VERSION 5.7 ;
  NOWIREEXTENSIONATPIN ON ;
  DIVIDERCHAR "/" ;
  BUSBITCHARS "[]" ;
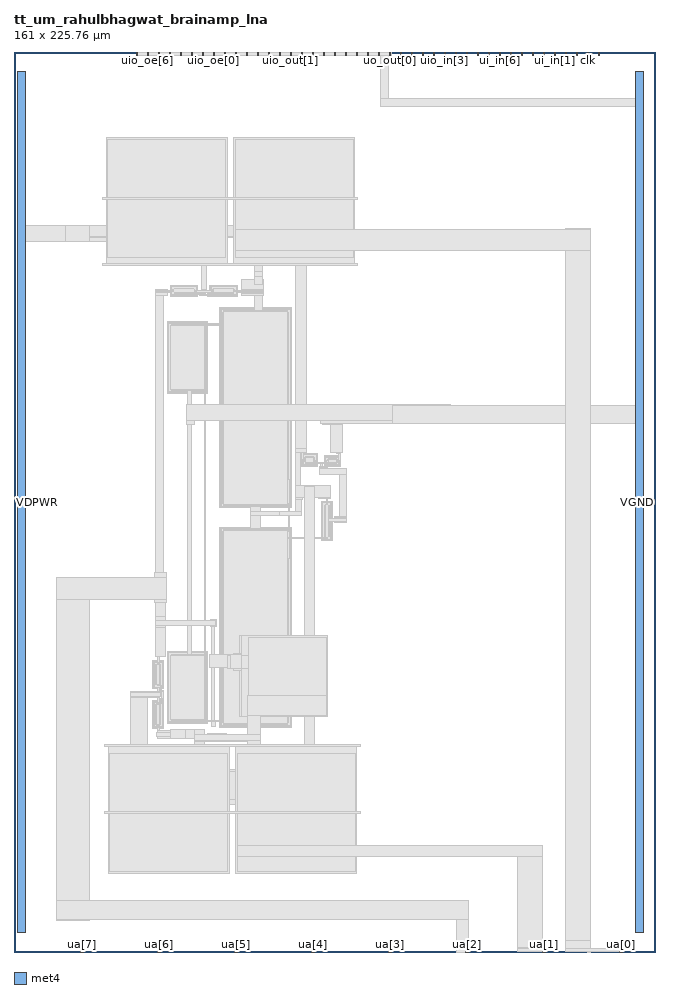
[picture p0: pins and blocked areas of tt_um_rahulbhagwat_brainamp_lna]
MACRO tt_um_rahulbhagwat_brainamp_lna
  CLASS BLOCK ;
  FOREIGN tt_um_rahulbhagwat_brainamp_lna ;
  ORIGIN 0.000 0.000 ;
  SIZE 161.000 BY 225.760 ;
  PIN clk
    DIRECTION INPUT ;
    USE SIGNAL ;
    PORT
      LAYER met4 ;
        RECT 143.830 224.760 144.130 225.760 ;
    END
  END clk
  PIN ena
    DIRECTION INPUT ;
    USE SIGNAL ;
    PORT
      LAYER met4 ;
        RECT 146.590 224.760 146.890 225.760 ;
    END
  END ena
  PIN rst_n
    DIRECTION INPUT ;
    USE SIGNAL ;
    PORT
      LAYER met4 ;
        RECT 141.070 224.760 141.370 225.760 ;
    END
  END rst_n
  PIN ua[0]
    DIRECTION INOUT ;
    USE SIGNAL ;
    PORT
      LAYER met4 ;
        RECT 151.810 0.000 152.710 1.000 ;
    END
  END ua[0]
  PIN ua[1]
    DIRECTION INOUT ;
    USE SIGNAL ;
    PORT
      LAYER met4 ;
        RECT 132.490 0.000 133.390 1.000 ;
    END
  END ua[1]
  PIN ua[2]
    DIRECTION INOUT ;
    USE SIGNAL ;
    ANTENNADIFFAREA 16.529999 ;
    PORT
      LAYER met4 ;
        RECT 113.170 0.000 114.070 1.000 ;
    END
  END ua[2]
  PIN ua[3]
    DIRECTION INOUT ;
    USE SIGNAL ;
    PORT
      LAYER met4 ;
        RECT 93.850 0.000 94.750 1.000 ;
    END
  END ua[3]
  PIN ua[4]
    DIRECTION INOUT ;
    USE SIGNAL ;
    PORT
      LAYER met4 ;
        RECT 74.530 0.000 75.430 1.000 ;
    END
  END ua[4]
  PIN ua[5]
    DIRECTION INOUT ;
    USE SIGNAL ;
    PORT
      LAYER met4 ;
        RECT 55.210 0.000 56.110 1.000 ;
    END
  END ua[5]
  PIN ua[6]
    DIRECTION INOUT ;
    USE SIGNAL ;
    PORT
      LAYER met4 ;
        RECT 35.890 0.000 36.790 1.000 ;
    END
  END ua[6]
  PIN ua[7]
    DIRECTION INOUT ;
    USE SIGNAL ;
    PORT
      LAYER met4 ;
        RECT 16.570 0.000 17.470 1.000 ;
    END
  END ua[7]
  PIN ui_in[0]
    DIRECTION INPUT ;
    USE SIGNAL ;
    PORT
      LAYER met4 ;
        RECT 138.310 224.760 138.610 225.760 ;
    END
  END ui_in[0]
  PIN ui_in[1]
    DIRECTION INPUT ;
    USE SIGNAL ;
    PORT
      LAYER met4 ;
        RECT 135.550 224.760 135.850 225.760 ;
    END
  END ui_in[1]
  PIN ui_in[2]
    DIRECTION INPUT ;
    USE SIGNAL ;
    PORT
      LAYER met4 ;
        RECT 132.790 224.760 133.090 225.760 ;
    END
  END ui_in[2]
  PIN ui_in[3]
    DIRECTION INPUT ;
    USE SIGNAL ;
    PORT
      LAYER met4 ;
        RECT 130.030 224.760 130.330 225.760 ;
    END
  END ui_in[3]
  PIN ui_in[4]
    DIRECTION INPUT ;
    USE SIGNAL ;
    PORT
      LAYER met4 ;
        RECT 127.270 224.760 127.570 225.760 ;
    END
  END ui_in[4]
  PIN ui_in[5]
    DIRECTION INPUT ;
    USE SIGNAL ;
    PORT
      LAYER met4 ;
        RECT 124.510 224.760 124.810 225.760 ;
    END
  END ui_in[5]
  PIN ui_in[6]
    DIRECTION INPUT ;
    USE SIGNAL ;
    PORT
      LAYER met4 ;
        RECT 121.750 224.760 122.050 225.760 ;
    END
  END ui_in[6]
  PIN ui_in[7]
    DIRECTION INPUT ;
    USE SIGNAL ;
    PORT
      LAYER met4 ;
        RECT 118.990 224.760 119.290 225.760 ;
    END
  END ui_in[7]
  PIN uio_in[0]
    DIRECTION INPUT ;
    USE SIGNAL ;
    PORT
      LAYER met4 ;
        RECT 116.230 224.760 116.530 225.760 ;
    END
  END uio_in[0]
  PIN uio_in[1]
    DIRECTION INPUT ;
    USE SIGNAL ;
    PORT
      LAYER met4 ;
        RECT 113.470 224.760 113.770 225.760 ;
    END
  END uio_in[1]
  PIN uio_in[2]
    DIRECTION INPUT ;
    USE SIGNAL ;
    PORT
      LAYER met4 ;
        RECT 110.710 224.760 111.010 225.760 ;
    END
  END uio_in[2]
  PIN uio_in[3]
    DIRECTION INPUT ;
    USE SIGNAL ;
    PORT
      LAYER met4 ;
        RECT 107.950 224.760 108.250 225.760 ;
    END
  END uio_in[3]
  PIN uio_in[4]
    DIRECTION INPUT ;
    USE SIGNAL ;
    PORT
      LAYER met4 ;
        RECT 105.190 224.760 105.490 225.760 ;
    END
  END uio_in[4]
  PIN uio_in[5]
    DIRECTION INPUT ;
    USE SIGNAL ;
    PORT
      LAYER met4 ;
        RECT 102.430 224.760 102.730 225.760 ;
    END
  END uio_in[5]
  PIN uio_in[6]
    DIRECTION INPUT ;
    USE SIGNAL ;
    PORT
      LAYER met4 ;
        RECT 99.670 224.760 99.970 225.760 ;
    END
  END uio_in[6]
  PIN uio_in[7]
    DIRECTION INPUT ;
    USE SIGNAL ;
    PORT
      LAYER met4 ;
        RECT 96.910 224.760 97.210 225.760 ;
    END
  END uio_in[7]
  PIN uio_oe[0]
    DIRECTION OUTPUT ;
    USE SIGNAL ;
    ANTENNADIFFAREA 25.014999 ;
    PORT
      LAYER met4 ;
        RECT 49.990 224.760 50.290 225.760 ;
    END
  END uio_oe[0]
  PIN uio_oe[1]
    DIRECTION OUTPUT ;
    USE SIGNAL ;
    PORT
      LAYER met4 ;
        RECT 47.230 224.760 47.530 225.760 ;
    END
  END uio_oe[1]
  PIN uio_oe[2]
    DIRECTION OUTPUT ;
    USE SIGNAL ;
    PORT
      LAYER met4 ;
        RECT 44.470 224.760 44.770 225.760 ;
    END
  END uio_oe[2]
  PIN uio_oe[3]
    DIRECTION OUTPUT ;
    USE SIGNAL ;
    PORT
      LAYER met4 ;
        RECT 41.710 224.760 42.010 225.760 ;
    END
  END uio_oe[3]
  PIN uio_oe[4]
    DIRECTION OUTPUT ;
    USE SIGNAL ;
    PORT
      LAYER met4 ;
        RECT 38.950 224.760 39.250 225.760 ;
    END
  END uio_oe[4]
  PIN uio_oe[5]
    DIRECTION OUTPUT ;
    USE SIGNAL ;
    PORT
      LAYER met4 ;
        RECT 36.190 224.760 36.490 225.760 ;
    END
  END uio_oe[5]
  PIN uio_oe[6]
    DIRECTION OUTPUT ;
    USE SIGNAL ;
    PORT
      LAYER met4 ;
        RECT 33.430 224.760 33.730 225.760 ;
    END
  END uio_oe[6]
  PIN uio_oe[7]
    DIRECTION OUTPUT ;
    USE SIGNAL ;
    PORT
      LAYER met4 ;
        RECT 30.670 224.760 30.970 225.760 ;
    END
  END uio_oe[7]
  PIN uio_out[0]
    DIRECTION OUTPUT ;
    USE SIGNAL ;
    ANTENNADIFFAREA 25.014999 ;
    PORT
      LAYER met4 ;
        RECT 72.070 224.760 72.370 225.760 ;
    END
  END uio_out[0]
  PIN uio_out[1]
    DIRECTION OUTPUT ;
    USE SIGNAL ;
    PORT
      LAYER met4 ;
        RECT 69.310 224.760 69.610 225.760 ;
    END
  END uio_out[1]
  PIN uio_out[2]
    DIRECTION OUTPUT ;
    USE SIGNAL ;
    PORT
      LAYER met4 ;
        RECT 66.550 224.760 66.850 225.760 ;
    END
  END uio_out[2]
  PIN uio_out[3]
    DIRECTION OUTPUT ;
    USE SIGNAL ;
    PORT
      LAYER met4 ;
        RECT 63.790 224.760 64.090 225.760 ;
    END
  END uio_out[3]
  PIN uio_out[4]
    DIRECTION OUTPUT ;
    USE SIGNAL ;
    PORT
      LAYER met4 ;
        RECT 61.030 224.760 61.330 225.760 ;
    END
  END uio_out[4]
  PIN uio_out[5]
    DIRECTION OUTPUT ;
    USE SIGNAL ;
    PORT
      LAYER met4 ;
        RECT 58.270 224.760 58.570 225.760 ;
    END
  END uio_out[5]
  PIN uio_out[6]
    DIRECTION OUTPUT ;
    USE SIGNAL ;
    PORT
      LAYER met4 ;
        RECT 55.510 224.760 55.810 225.760 ;
    END
  END uio_out[6]
  PIN uio_out[7]
    DIRECTION OUTPUT ;
    USE SIGNAL ;
    PORT
      LAYER met4 ;
        RECT 52.750 224.760 53.050 225.760 ;
    END
  END uio_out[7]
  PIN uo_out[0]
    DIRECTION OUTPUT ;
    USE SIGNAL ;
    ANTENNADIFFAREA 25.014999 ;
    PORT
      LAYER met4 ;
        RECT 94.150 224.760 94.450 225.760 ;
    END
  END uo_out[0]
  PIN uo_out[1]
    DIRECTION OUTPUT ;
    USE SIGNAL ;
    ANTENNADIFFAREA 25.014999 ;
    PORT
      LAYER met4 ;
        RECT 91.390 224.760 91.690 225.760 ;
    END
  END uo_out[1]
  PIN uo_out[2]
    DIRECTION OUTPUT ;
    USE SIGNAL ;
    PORT
      LAYER met4 ;
        RECT 88.630 224.760 88.930 225.760 ;
    END
  END uo_out[2]
  PIN uo_out[3]
    DIRECTION OUTPUT ;
    USE SIGNAL ;
    PORT
      LAYER met4 ;
        RECT 85.870 224.760 86.170 225.760 ;
    END
  END uo_out[3]
  PIN uo_out[4]
    DIRECTION OUTPUT ;
    USE SIGNAL ;
    PORT
      LAYER met4 ;
        RECT 83.110 224.760 83.410 225.760 ;
    END
  END uo_out[4]
  PIN uo_out[5]
    DIRECTION OUTPUT ;
    USE SIGNAL ;
    PORT
      LAYER met4 ;
        RECT 80.350 224.760 80.650 225.760 ;
    END
  END uo_out[5]
  PIN uo_out[6]
    DIRECTION OUTPUT ;
    USE SIGNAL ;
    PORT
      LAYER met4 ;
        RECT 77.590 224.760 77.890 225.760 ;
    END
  END uo_out[6]
  PIN uo_out[7]
    DIRECTION OUTPUT ;
    USE SIGNAL ;
    PORT
      LAYER met4 ;
        RECT 74.830 224.760 75.130 225.760 ;
    END
  END uo_out[7]
  PIN VDPWR
    DIRECTION INOUT ;
    USE POWER ;
    PORT
      LAYER met4 ;
        RECT 1.000 5.000 3.000 220.760 ;
    END
  END VDPWR
  PIN VGND
    DIRECTION INOUT ;
    USE GROUND ;
    PORT
      LAYER met4 ;
        RECT 156.000 5.000 158.000 220.760 ;
    END
  END VGND
  OBS
      LAYER nwell ;
        RECT 39.160 164.530 46.120 167.220 ;
        RECT 49.125 164.515 56.085 167.205 ;
      LAYER pwell ;
        RECT 38.490 140.150 48.590 158.110 ;
      LAYER nwell ;
        RECT 51.650 111.400 69.610 161.590 ;
        RECT 72.170 121.845 76.130 125.035 ;
      LAYER pwell ;
        RECT 77.865 121.850 81.825 124.450 ;
      LAYER nwell ;
        RECT 34.805 66.065 37.495 73.025 ;
        RECT 34.790 56.100 37.480 63.060 ;
      LAYER pwell ;
        RECT 38.490 57.400 48.590 75.360 ;
      LAYER nwell ;
        RECT 51.650 56.400 69.610 106.590 ;
        RECT 77.150 103.130 79.840 113.090 ;
      LAYER li1 ;
        RECT 39.340 166.870 45.940 167.040 ;
        RECT 37.320 165.490 37.920 165.990 ;
        RECT 39.340 164.880 39.510 166.870 ;
        RECT 40.140 166.360 45.140 166.530 ;
        RECT 39.910 165.605 40.080 166.145 ;
        RECT 45.200 165.605 45.370 166.145 ;
        RECT 45.770 165.840 45.940 166.870 ;
        RECT 49.305 166.855 55.905 167.025 ;
        RECT 45.770 165.590 46.070 165.840 ;
        RECT 40.140 165.220 45.140 165.390 ;
        RECT 45.770 164.880 45.940 165.590 ;
        RECT 47.320 165.490 47.920 165.990 ;
        RECT 49.305 165.890 49.475 166.855 ;
        RECT 50.105 166.345 55.105 166.515 ;
        RECT 49.170 165.540 49.475 165.890 ;
        RECT 49.875 165.590 50.045 166.130 ;
        RECT 55.165 165.590 55.335 166.130 ;
        RECT 39.340 164.710 45.940 164.880 ;
        RECT 49.305 164.865 49.475 165.540 ;
        RECT 50.105 165.205 55.105 165.375 ;
        RECT 55.735 164.865 55.905 166.855 ;
        RECT 57.470 165.440 57.820 165.940 ;
        RECT 49.305 164.695 55.905 164.865 ;
        RECT 51.830 161.240 69.430 161.410 ;
        RECT 38.670 157.760 48.410 157.930 ;
        RECT 38.670 140.500 38.840 157.760 ;
        RECT 39.520 157.190 47.560 157.360 ;
        RECT 39.180 141.130 39.350 157.130 ;
        RECT 47.730 141.130 47.900 157.130 ;
        RECT 39.520 140.900 47.560 141.070 ;
        RECT 48.240 140.500 48.410 157.760 ;
        RECT 38.670 140.330 48.410 140.500 ;
        RECT 43.850 140.190 44.350 140.330 ;
        RECT 51.830 111.750 52.000 161.240 ;
        RECT 52.630 160.730 68.630 160.900 ;
        RECT 52.400 112.475 52.570 160.515 ;
        RECT 68.690 112.475 68.860 160.515 ;
        RECT 52.630 112.090 68.630 112.260 ;
        RECT 69.260 111.750 69.430 161.240 ;
        RECT 72.290 125.470 72.980 126.200 ;
        RECT 81.185 125.260 81.930 126.125 ;
        RECT 72.350 124.685 75.950 124.855 ;
        RECT 72.350 123.520 72.520 124.685 ;
        RECT 73.150 124.175 75.150 124.345 ;
        RECT 72.310 123.270 72.520 123.520 ;
        RECT 72.350 122.195 72.520 123.270 ;
        RECT 72.920 122.920 73.090 123.960 ;
        RECT 75.210 122.920 75.380 123.960 ;
        RECT 73.150 122.535 75.150 122.705 ;
        RECT 75.780 122.195 75.950 124.685 ;
        RECT 72.350 122.025 75.950 122.195 ;
        RECT 78.045 124.100 81.645 124.270 ;
        RECT 78.045 122.200 78.215 124.100 ;
        RECT 78.845 123.590 80.845 123.760 ;
        RECT 78.615 122.880 78.785 123.420 ;
        RECT 80.905 122.880 81.075 123.420 ;
        RECT 81.475 123.265 81.645 124.100 ;
        RECT 81.475 123.020 81.685 123.265 ;
        RECT 78.845 122.540 80.845 122.710 ;
        RECT 81.475 122.200 81.645 123.020 ;
        RECT 78.045 122.030 81.645 122.200 ;
        RECT 76.925 120.910 77.415 121.530 ;
        RECT 78.350 112.910 78.650 113.090 ;
        RECT 51.830 111.580 69.430 111.750 ;
        RECT 77.330 112.740 79.660 112.910 ;
        RECT 60.050 111.390 61.150 111.580 ;
        RECT 60.050 106.410 61.150 106.590 ;
        RECT 51.830 106.240 69.430 106.410 ;
        RECT 43.750 75.180 44.350 75.390 ;
        RECT 38.670 75.010 48.410 75.180 ;
        RECT 36.070 74.410 36.570 74.760 ;
        RECT 34.985 72.675 37.315 72.845 ;
        RECT 34.985 66.415 35.155 72.675 ;
        RECT 35.880 72.105 36.420 72.275 ;
        RECT 35.495 67.045 35.665 72.045 ;
        RECT 36.635 67.045 36.805 72.045 ;
        RECT 35.880 66.815 36.420 66.985 ;
        RECT 37.145 66.415 37.315 72.675 ;
        RECT 34.985 66.245 37.315 66.415 ;
        RECT 36.120 66.110 36.470 66.245 ;
        RECT 36.020 64.260 36.520 64.860 ;
        RECT 36.170 62.880 36.420 63.010 ;
        RECT 34.970 62.710 37.300 62.880 ;
        RECT 34.970 56.450 35.140 62.710 ;
        RECT 35.865 62.140 36.405 62.310 ;
        RECT 35.480 57.080 35.650 62.080 ;
        RECT 36.620 57.080 36.790 62.080 ;
        RECT 35.865 56.850 36.405 57.020 ;
        RECT 37.130 56.450 37.300 62.710 ;
        RECT 38.670 57.750 38.840 75.010 ;
        RECT 43.750 74.990 44.350 75.010 ;
        RECT 39.520 74.440 47.560 74.610 ;
        RECT 39.180 58.380 39.350 74.380 ;
        RECT 47.730 58.380 47.900 74.380 ;
        RECT 39.520 58.150 47.560 58.320 ;
        RECT 48.240 57.750 48.410 75.010 ;
        RECT 38.670 57.580 48.410 57.750 ;
        RECT 51.830 56.750 52.000 106.240 ;
        RECT 52.630 105.730 68.630 105.900 ;
        RECT 52.400 57.475 52.570 105.515 ;
        RECT 68.690 57.475 68.860 105.515 ;
        RECT 52.630 57.090 68.630 57.260 ;
        RECT 69.260 56.750 69.430 106.240 ;
        RECT 77.330 103.480 77.500 112.740 ;
        RECT 78.225 112.170 78.765 112.340 ;
        RECT 77.840 104.110 78.010 112.110 ;
        RECT 78.980 104.110 79.150 112.110 ;
        RECT 78.225 103.880 78.765 104.050 ;
        RECT 79.490 103.480 79.660 112.740 ;
        RECT 77.330 103.310 79.660 103.480 ;
        RECT 51.830 56.580 69.430 56.750 ;
        RECT 34.970 56.280 37.300 56.450 ;
        RECT 36.020 54.260 36.520 54.860 ;
      LAYER met1 ;
        RECT 70.350 182.330 74.480 182.370 ;
        RECT 47.120 182.300 74.480 182.330 ;
        RECT 47.080 182.210 74.480 182.300 ;
        RECT 18.040 182.140 74.480 182.210 ;
        RECT 13.940 179.360 74.480 182.140 ;
        RECT 13.940 179.230 73.410 179.360 ;
        RECT 13.940 178.260 48.460 179.230 ;
        RECT 18.040 178.220 48.460 178.260 ;
        RECT 18.040 178.210 48.410 178.220 ;
        RECT 40.160 166.330 45.120 166.560 ;
        RECT 47.110 166.290 48.400 178.210 ;
        RECT 50.125 166.315 55.085 166.545 ;
        RECT 35.500 165.990 38.460 166.230 ;
        RECT 39.880 165.990 40.110 166.125 ;
        RECT 35.500 165.690 40.110 165.990 ;
        RECT 35.500 165.490 39.470 165.690 ;
        RECT 39.880 165.625 40.110 165.690 ;
        RECT 45.170 166.035 45.400 166.125 ;
        RECT 45.170 165.710 45.420 166.035 ;
        RECT 47.040 165.990 48.400 166.290 ;
        RECT 57.150 166.190 62.470 168.730 ;
        RECT 45.170 165.625 45.470 165.710 ;
        RECT 35.500 164.750 38.460 165.490 ;
        RECT 40.160 165.390 45.120 165.420 ;
        RECT 45.270 165.390 45.470 165.625 ;
        RECT 45.770 165.490 49.470 165.990 ;
        RECT 49.845 165.940 50.075 166.110 ;
        RECT 49.820 165.610 50.075 165.940 ;
        RECT 55.135 165.940 55.365 166.110 ;
        RECT 57.120 165.940 62.470 166.190 ;
        RECT 55.135 165.690 62.470 165.940 ;
        RECT 55.135 165.610 55.365 165.690 ;
        RECT 40.160 165.340 45.470 165.390 ;
        RECT 40.160 165.280 45.480 165.340 ;
        RECT 40.160 165.220 46.720 165.280 ;
        RECT 40.160 165.190 45.120 165.220 ;
        RECT 45.310 165.050 46.720 165.220 ;
        RECT 47.120 165.190 48.120 165.490 ;
        RECT 49.820 165.385 49.970 165.610 ;
        RECT 55.770 165.440 62.470 165.690 ;
        RECT 50.125 165.385 55.085 165.405 ;
        RECT 49.770 165.290 55.085 165.385 ;
        RECT 48.535 165.280 55.085 165.290 ;
        RECT 45.310 165.040 45.480 165.050 ;
        RECT 46.425 164.975 46.720 165.050 ;
        RECT 48.525 165.180 55.085 165.280 ;
        RECT 57.120 165.190 62.470 165.440 ;
        RECT 48.525 165.070 49.965 165.180 ;
        RECT 50.125 165.175 55.085 165.180 ;
        RECT 48.525 164.975 48.710 165.070 ;
        RECT 49.775 165.035 49.965 165.070 ;
        RECT 35.520 83.300 37.450 164.750 ;
        RECT 46.425 164.570 48.710 164.975 ;
        RECT 57.150 164.680 62.470 165.190 ;
        RECT 46.430 164.560 48.710 164.570 ;
        RECT 48.525 164.545 48.710 164.560 ;
        RECT 60.230 160.930 62.460 164.680 ;
        RECT 52.650 160.700 68.610 160.930 ;
        RECT 60.230 160.580 62.460 160.700 ;
        RECT 52.370 157.540 52.600 160.495 ;
        RECT 46.700 157.390 52.600 157.540 ;
        RECT 39.540 157.190 52.600 157.390 ;
        RECT 39.540 157.160 47.540 157.190 ;
        RECT 47.700 157.140 52.600 157.190 ;
        RECT 39.150 141.150 39.380 157.110 ;
        RECT 47.700 156.640 48.000 157.140 ;
        RECT 47.700 142.240 47.930 156.640 ;
        RECT 47.700 141.150 48.100 142.240 ;
        RECT 39.540 140.870 47.540 141.100 ;
        RECT 43.550 137.280 44.650 140.870 ;
        RECT 43.390 132.280 45.390 137.280 ;
        RECT 35.510 74.120 37.950 83.300 ;
        RECT 43.550 74.640 44.650 132.280 ;
        RECT 39.540 74.410 47.540 74.640 ;
        RECT 47.750 74.360 48.100 141.150 ;
        RECT 52.370 112.495 52.600 157.140 ;
        RECT 68.660 118.490 68.890 160.495 ;
        RECT 70.570 126.220 73.410 179.230 ;
        RECT 77.390 132.280 81.390 137.280 ;
        RECT 70.650 125.300 73.310 126.220 ;
        RECT 68.660 112.495 69.050 118.490 ;
        RECT 52.650 112.060 68.610 112.290 ;
        RECT 59.250 110.590 61.850 111.790 ;
        RECT 59.250 109.590 67.650 110.590 ;
        RECT 59.250 106.190 61.850 109.590 ;
        RECT 52.650 105.700 68.610 105.930 ;
        RECT 68.750 105.495 69.050 112.495 ;
        RECT 70.650 116.920 71.790 125.300 ;
        RECT 72.230 123.570 72.725 125.300 ;
        RECT 79.390 125.280 82.390 132.280 ;
        RECT 81.020 125.165 82.020 125.280 ;
        RECT 73.170 124.145 75.130 124.375 ;
        RECT 72.890 123.570 73.120 123.940 ;
        RECT 72.230 123.220 73.120 123.570 ;
        RECT 72.230 123.215 72.725 123.220 ;
        RECT 72.890 122.940 73.120 123.220 ;
        RECT 75.180 123.320 75.410 123.940 ;
        RECT 78.865 123.560 80.825 123.790 ;
        RECT 75.180 122.940 75.615 123.320 ;
        RECT 78.585 123.230 78.815 123.400 ;
        RECT 73.170 122.710 75.130 122.735 ;
        RECT 75.325 122.710 75.615 122.940 ;
        RECT 78.445 122.900 78.815 123.230 ;
        RECT 80.875 123.345 81.105 123.400 ;
        RECT 81.475 123.345 81.785 125.165 ;
        RECT 80.875 122.975 81.785 123.345 ;
        RECT 80.875 122.960 81.740 122.975 ;
        RECT 80.875 122.900 81.105 122.960 ;
        RECT 78.445 122.710 78.695 122.900 ;
        RECT 78.865 122.710 80.825 122.740 ;
        RECT 73.170 122.510 80.825 122.710 ;
        RECT 73.170 122.505 79.345 122.510 ;
        RECT 74.725 122.420 79.345 122.505 ;
        RECT 76.825 121.690 77.495 122.420 ;
        RECT 76.635 121.570 77.635 121.690 ;
        RECT 76.630 121.300 78.520 121.570 ;
        RECT 76.630 119.750 83.520 121.300 ;
        RECT 76.630 119.720 78.520 119.750 ;
        RECT 76.490 116.920 79.370 116.940 ;
        RECT 70.650 114.090 79.370 116.920 ;
        RECT 70.650 113.600 72.360 114.090 ;
        RECT 76.490 113.700 79.370 114.090 ;
        RECT 70.650 109.590 72.150 113.600 ;
        RECT 78.300 112.370 78.700 113.700 ;
        RECT 79.150 113.690 79.370 113.700 ;
        RECT 78.245 112.140 78.745 112.370 ;
        RECT 49.390 81.550 50.820 83.530 ;
        RECT 35.820 74.060 36.820 74.120 ;
        RECT 36.070 72.710 36.570 74.060 ;
        RECT 36.070 72.305 36.320 72.710 ;
        RECT 35.900 72.075 36.400 72.305 ;
        RECT 35.465 67.065 35.695 72.025 ;
        RECT 36.605 67.065 36.835 72.025 ;
        RECT 35.900 66.910 36.400 67.015 ;
        RECT 36.625 66.910 36.830 67.065 ;
        RECT 35.900 66.905 36.830 66.910 ;
        RECT 35.900 66.785 36.975 66.905 ;
        RECT 36.070 66.760 36.975 66.785 ;
        RECT 36.625 66.715 36.975 66.760 ;
        RECT 36.625 66.710 36.940 66.715 ;
        RECT 29.320 65.300 33.370 65.310 ;
        RECT 36.020 65.300 36.520 66.410 ;
        RECT 36.720 65.650 36.940 66.710 ;
        RECT 36.720 65.475 37.465 65.650 ;
        RECT 36.730 65.465 37.465 65.475 ;
        RECT 29.320 65.060 36.520 65.300 ;
        RECT 29.320 64.060 36.820 65.060 ;
        RECT 29.320 63.960 36.520 64.060 ;
        RECT 29.320 45.280 33.370 63.960 ;
        RECT 36.020 62.710 36.520 63.960 ;
        RECT 37.035 63.660 37.450 65.465 ;
        RECT 36.730 63.370 37.450 63.660 ;
        RECT 36.730 63.365 37.440 63.370 ;
        RECT 36.730 62.420 36.960 63.365 ;
        RECT 36.670 62.410 36.970 62.420 ;
        RECT 36.300 62.360 36.970 62.410 ;
        RECT 35.975 62.340 36.970 62.360 ;
        RECT 35.885 62.250 36.970 62.340 ;
        RECT 35.885 62.210 36.790 62.250 ;
        RECT 35.885 62.110 36.385 62.210 ;
        RECT 36.620 62.060 36.790 62.210 ;
        RECT 35.450 57.100 35.680 62.060 ;
        RECT 36.590 57.100 36.820 62.060 ;
        RECT 39.150 58.400 39.380 74.360 ;
        RECT 47.700 72.990 48.100 74.360 ;
        RECT 47.700 58.400 47.930 72.990 ;
        RECT 39.540 58.190 47.540 58.350 ;
        RECT 49.600 58.190 50.360 81.550 ;
        RECT 52.370 58.190 52.600 105.495 ;
        RECT 68.660 103.990 69.050 105.495 ;
        RECT 77.810 104.130 78.040 112.090 ;
        RECT 78.950 108.690 79.180 112.090 ;
        RECT 81.690 109.220 83.520 119.750 ;
        RECT 80.360 108.910 83.520 109.220 ;
        RECT 80.360 108.790 83.430 108.910 ;
        RECT 80.350 108.690 83.430 108.790 ;
        RECT 78.950 107.990 83.430 108.690 ;
        RECT 78.950 104.130 79.180 107.990 ;
        RECT 80.350 107.790 83.430 107.990 ;
        RECT 80.360 107.780 83.430 107.790 ;
        RECT 78.245 103.990 78.745 104.080 ;
        RECT 68.650 103.790 78.750 103.990 ;
        RECT 39.540 58.120 52.600 58.190 ;
        RECT 46.750 57.890 52.600 58.120 ;
        RECT 35.885 56.820 36.385 57.050 ;
        RECT 36.020 56.410 36.320 56.820 ;
        RECT 49.550 56.490 50.550 57.890 ;
        RECT 52.370 57.495 52.600 57.890 ;
        RECT 68.660 98.790 69.050 103.790 ;
        RECT 68.660 57.495 68.890 98.790 ;
        RECT 52.650 57.060 68.610 57.290 ;
        RECT 36.020 55.560 36.520 56.410 ;
        RECT 35.930 55.060 42.490 55.560 ;
        RECT 60.150 55.330 61.150 57.060 ;
        RECT 35.820 54.060 42.490 55.060 ;
        RECT 60.000 54.650 61.390 55.330 ;
        RECT 35.930 53.550 42.490 54.060 ;
        RECT 53.760 52.860 61.390 54.650 ;
        RECT 53.720 45.280 77.830 45.820 ;
        RECT 29.320 38.160 77.830 45.280 ;
        RECT 29.330 38.140 77.830 38.160 ;
        RECT 53.720 37.060 77.830 38.140 ;
      LAYER met2 ;
        RECT 9.540 178.230 19.050 182.260 ;
        RECT 60.400 167.320 62.400 170.300 ;
        RECT 43.390 137.270 81.390 137.280 ;
        RECT 43.390 133.280 109.580 137.270 ;
        RECT 76.840 132.650 109.580 133.280 ;
        RECT 66.650 109.590 72.150 110.590 ;
        RECT 35.410 83.260 37.910 87.280 ;
        RECT 35.410 81.790 50.650 83.260 ;
        RECT 35.410 81.350 37.910 81.790 ;
        RECT 49.090 74.530 50.870 74.560 ;
        RECT 49.090 71.310 55.100 74.530 ;
        RECT 49.090 71.290 50.870 71.310 ;
        RECT 39.370 53.530 45.350 55.720 ;
        RECT 51.290 52.890 55.520 54.660 ;
        RECT 72.830 44.180 75.310 116.760 ;
        RECT 72.670 37.220 76.710 44.180 ;
      LAYER met3 ;
        RECT 1.020 178.260 12.940 182.360 ;
        RECT 23.080 172.130 53.480 204.290 ;
        RECT 55.080 172.130 85.480 204.290 ;
        RECT 60.380 169.390 62.370 171.720 ;
        RECT 95.050 137.050 149.300 137.060 ;
        RECT 95.050 132.570 157.950 137.050 ;
        RECT 95.050 132.510 157.780 132.570 ;
        RECT 95.050 132.450 149.300 132.510 ;
        RECT 35.430 84.270 37.930 91.370 ;
        RECT 56.550 74.500 78.710 79.380 ;
        RECT 53.470 71.210 78.710 74.500 ;
        RECT 56.550 58.980 78.710 71.210 ;
        RECT 42.950 53.570 47.800 55.850 ;
        RECT 48.520 52.890 53.320 54.810 ;
        RECT 23.620 19.810 54.020 51.970 ;
        RECT 55.620 19.810 86.020 51.970 ;
      LAYER met4 ;
        RECT 30.660 224.760 30.670 225.740 ;
        RECT 30.970 224.760 33.430 225.740 ;
        RECT 33.730 224.760 36.190 225.740 ;
        RECT 36.490 224.760 38.950 225.740 ;
        RECT 39.250 224.760 41.710 225.740 ;
        RECT 42.010 224.760 44.470 225.740 ;
        RECT 44.770 224.760 47.230 225.740 ;
        RECT 47.530 224.760 49.990 225.740 ;
        RECT 50.290 224.760 52.750 225.740 ;
        RECT 53.050 224.760 55.510 225.740 ;
        RECT 55.810 224.760 58.270 225.740 ;
        RECT 58.570 224.760 61.030 225.740 ;
        RECT 61.330 224.760 63.790 225.740 ;
        RECT 64.090 224.760 66.550 225.740 ;
        RECT 66.850 224.760 69.310 225.740 ;
        RECT 69.610 224.760 72.070 225.740 ;
        RECT 72.370 224.760 74.830 225.740 ;
        RECT 75.130 224.760 77.590 225.740 ;
        RECT 77.890 224.760 80.350 225.740 ;
        RECT 80.650 224.760 83.110 225.740 ;
        RECT 83.410 224.760 85.870 225.740 ;
        RECT 86.170 224.760 88.630 225.740 ;
        RECT 88.930 224.760 91.390 225.740 ;
        RECT 91.690 224.760 94.150 225.740 ;
        RECT 94.450 224.760 94.650 225.740 ;
        RECT 92.000 214.000 93.990 224.760 ;
        RECT 91.980 211.990 156.000 214.000 ;
        RECT 23.475 189.350 53.085 203.895 ;
        RECT 55.475 189.350 85.085 203.895 ;
        RECT 22.280 188.830 86.280 189.350 ;
        RECT 23.475 174.285 53.085 188.830 ;
        RECT 55.475 181.290 85.085 188.830 ;
        RECT 138.350 181.290 144.670 181.460 ;
        RECT 55.475 175.850 144.670 181.290 ;
        RECT 55.475 174.285 85.085 175.850 ;
        RECT 60.380 172.650 62.370 172.660 ;
        RECT 22.280 172.130 86.280 172.650 ;
        RECT 60.380 170.740 62.370 172.130 ;
        RECT 11.970 93.980 15.940 94.000 ;
        RECT 35.350 93.980 38.310 95.240 ;
        RECT 11.970 93.970 38.310 93.980 ;
        RECT 10.760 88.430 38.310 93.970 ;
        RECT 10.760 13.040 18.870 88.430 ;
        RECT 35.350 87.650 38.310 88.430 ;
        RECT 56.570 74.960 57.050 79.320 ;
        RECT 55.150 74.570 57.050 74.960 ;
        RECT 54.430 74.510 57.050 74.570 ;
        RECT 54.280 71.220 57.050 74.510 ;
        RECT 54.430 71.140 57.050 71.220 ;
        RECT 55.150 70.500 57.050 71.140 ;
        RECT 56.570 59.040 57.050 70.500 ;
        RECT 58.705 64.360 78.315 78.985 ;
        RECT 58.530 59.375 78.315 64.360 ;
        RECT 45.400 54.650 47.790 55.920 ;
        RECT 45.400 54.630 50.400 54.650 ;
        RECT 58.530 54.630 61.870 59.375 ;
        RECT 45.400 53.010 61.890 54.630 ;
        RECT 45.400 52.880 50.400 53.010 ;
        RECT 45.400 51.970 47.790 52.880 ;
        RECT 58.530 51.970 61.870 53.010 ;
        RECT 22.820 51.450 86.820 51.970 ;
        RECT 24.015 35.270 53.625 49.815 ;
        RECT 56.015 35.270 85.625 49.815 ;
        RECT 22.820 34.750 86.820 35.270 ;
        RECT 24.015 20.205 53.625 34.750 ;
        RECT 56.015 26.680 85.625 34.750 ;
        RECT 56.015 24.070 132.470 26.680 ;
        RECT 56.015 20.205 85.625 24.070 ;
        RECT 10.700 13.000 111.970 13.040 ;
        RECT 10.700 8.050 114.000 13.000 ;
        RECT 10.760 7.970 18.870 8.050 ;
        RECT 111.000 1.000 114.000 8.050 ;
        RECT 126.270 1.030 132.470 24.070 ;
        RECT 138.350 2.960 144.670 175.850 ;
        RECT 126.270 1.000 133.390 1.030 ;
        RECT 138.350 1.000 144.690 2.960 ;
        RECT 111.000 0.000 113.170 1.000 ;
        RECT 126.270 0.060 132.490 1.000 ;
        RECT 138.350 0.990 144.710 1.000 ;
        RECT 138.350 0.060 151.810 0.990 ;
        RECT 129.520 0.040 132.490 0.060 ;
        RECT 140.950 0.030 151.810 0.060 ;
        RECT 142.990 0.020 151.810 0.030 ;
        RECT 143.810 0.000 144.710 0.020 ;
  END
END tt_um_rahulbhagwat_brainamp_lna
END LIBRARY

